One B-rep face of a CAD part: STEP entity #5143.
In plain terms, the planar face has unit normal (-1, 0, 0).
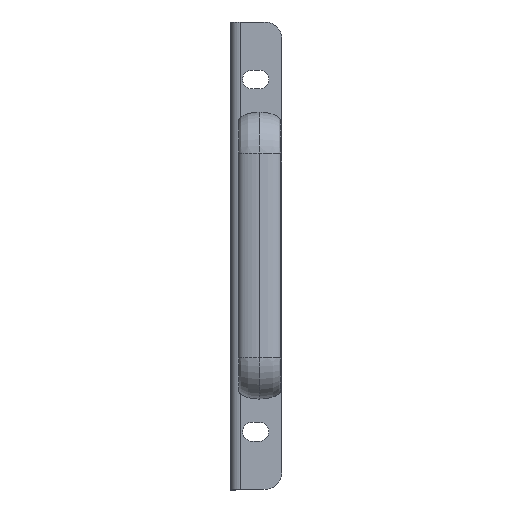
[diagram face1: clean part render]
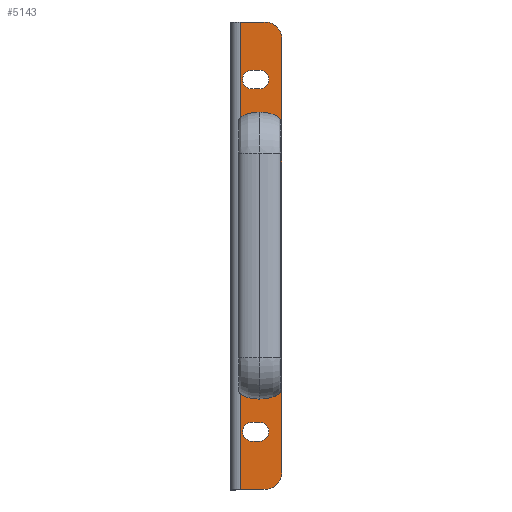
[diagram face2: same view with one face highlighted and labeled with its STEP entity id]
Its self-contained STEP definition (entity closure, numbers rounded to 3 decimals):
#1774=DIRECTION('',(0.,-1.,0.));
#1775=VECTOR('',#1774,177.);
#1776=CARTESIAN_POINT('',(0.,88.5,1.9));
#1777=LINE('',#1776,#1775);
#1792=CARTESIAN_POINT('',(0.,-66.7,6.304));
#1793=DIRECTION('',(-1.,0.,0.));
#1794=DIRECTION('',(0.,1.,0.));
#1795=AXIS2_PLACEMENT_3D('',#1792,#1793,#1794);
#1797=DIRECTION('',(0.,0.,-1.));
#1798=VECTOR('',#1797,2.9);
#1799=CARTESIAN_POINT('',(0.,-70.25,9.204));
#1800=LINE('',#1799,#1798);
#1801=CARTESIAN_POINT('',(0.,-66.7,9.204));
#1802=DIRECTION('',(-1.,0.,0.));
#1803=DIRECTION('',(0.,-1.,0.));
#1804=AXIS2_PLACEMENT_3D('',#1801,#1802,#1803);
#1806=DIRECTION('',(0.,0.,1.));
#1807=VECTOR('',#1806,2.9);
#1808=CARTESIAN_POINT('',(0.,-63.15,6.304));
#1809=LINE('',#1808,#1807);
#1810=DIRECTION('',(0.,0.,1.));
#1811=VECTOR('',#1810,2.9);
#1812=CARTESIAN_POINT('',(0.,70.25,6.304));
#1813=LINE('',#1812,#1811);
#1814=CARTESIAN_POINT('',(0.,66.7,6.304));
#1815=DIRECTION('',(-1.,0.,0.));
#1816=DIRECTION('',(0.,1.,0.));
#1817=AXIS2_PLACEMENT_3D('',#1814,#1815,#1816);
#1819=DIRECTION('',(0.,0.,-1.));
#1820=VECTOR('',#1819,2.9);
#1821=CARTESIAN_POINT('',(0.,63.15,9.204));
#1822=LINE('',#1821,#1820);
#1823=CARTESIAN_POINT('',(0.,66.7,9.204));
#1824=DIRECTION('',(-1.,0.,0.));
#1825=DIRECTION('',(0.,-1.,0.));
#1826=AXIS2_PLACEMENT_3D('',#1823,#1824,#1825);
#1828=CARTESIAN_POINT('',(0.,82.15,11.283));
#1829=DIRECTION('',(-1.,0.,0.));
#1830=DIRECTION('',(0.,0.,1.));
#1831=AXIS2_PLACEMENT_3D('',#1828,#1829,#1830);
#1833=DIRECTION('',(0.,1.,0.));
#1834=VECTOR('',#1833,164.3);
#1835=CARTESIAN_POINT('',(0.,-82.15,17.633));
#1836=LINE('',#1835,#1834);
#1837=CARTESIAN_POINT('',(0.,-82.15,11.283));
#1838=DIRECTION('',(-1.,0.,0.));
#1839=DIRECTION('',(0.,-1.,0.));
#1840=AXIS2_PLACEMENT_3D('',#1837,#1838,#1839);
#1842=DIRECTION('',(0.,0.,1.));
#1843=VECTOR('',#1842,9.383);
#1844=CARTESIAN_POINT('',(0.,-88.5,1.9));
#1845=LINE('',#1844,#1843);
#1846=DIRECTION('',(0.,0.,-1.));
#1847=VECTOR('',#1846,9.383);
#1848=CARTESIAN_POINT('',(0.,88.5,11.283));
#1849=LINE('',#1848,#1847);
#1850=CARTESIAN_POINT('',(0.,50.8,9.382));
#1851=DIRECTION('',(1.,0.,0.));
#1852=DIRECTION('',(0.,0.,1.));
#1853=AXIS2_PLACEMENT_3D('',#1850,#1851,#1852);
#1855=CARTESIAN_POINT('',(0.,50.8,9.382));
#1856=DIRECTION('',(1.,0.,0.));
#1857=DIRECTION('',(0.,0.,-1.));
#1858=AXIS2_PLACEMENT_3D('',#1855,#1856,#1857);
#1860=CARTESIAN_POINT('',(0.,-50.8,9.382));
#1861=DIRECTION('',(1.,0.,0.));
#1862=DIRECTION('',(0.,0.,1.));
#1863=AXIS2_PLACEMENT_3D('',#1860,#1861,#1862);
#1865=CARTESIAN_POINT('',(0.,-50.8,9.382));
#1866=DIRECTION('',(1.,0.,0.));
#1867=DIRECTION('',(0.,0.,-1.));
#1868=AXIS2_PLACEMENT_3D('',#1865,#1866,#1867);
#2294=CARTESIAN_POINT('',(0.,88.5,1.9));
#2295=CARTESIAN_POINT('',(0.,-88.5,1.9));
#2296=VERTEX_POINT('',#2294);
#2297=VERTEX_POINT('',#2295);
#2326=CARTESIAN_POINT('',(0.,70.25,6.304));
#2327=CARTESIAN_POINT('',(0.,70.25,9.204));
#2328=VERTEX_POINT('',#2326);
#2329=VERTEX_POINT('',#2327);
#2330=CARTESIAN_POINT('',(0.,63.15,9.204));
#2331=VERTEX_POINT('',#2330);
#2332=CARTESIAN_POINT('',(0.,63.15,6.304));
#2333=VERTEX_POINT('',#2332);
#2334=CARTESIAN_POINT('',(0.,-63.15,6.304));
#2335=CARTESIAN_POINT('',(0.,-70.25,6.304));
#2336=VERTEX_POINT('',#2334);
#2337=VERTEX_POINT('',#2335);
#2338=CARTESIAN_POINT('',(0.,-63.15,9.204));
#2339=VERTEX_POINT('',#2338);
#2340=CARTESIAN_POINT('',(0.,-70.25,9.204));
#2341=VERTEX_POINT('',#2340);
#2342=CARTESIAN_POINT('',(0.,82.15,17.633));
#2343=CARTESIAN_POINT('',(0.,88.5,11.283));
#2344=VERTEX_POINT('',#2342);
#2345=VERTEX_POINT('',#2343);
#2350=CARTESIAN_POINT('',(0.,-88.5,11.283));
#2351=CARTESIAN_POINT('',(0.,-82.15,17.633));
#2352=VERTEX_POINT('',#2350);
#2353=VERTEX_POINT('',#2351);
#2598=CARTESIAN_POINT('',(0.,-50.8,12.353));
#2599=CARTESIAN_POINT('',(0.,-50.8,6.41));
#2600=VERTEX_POINT('',#2598);
#2601=VERTEX_POINT('',#2599);
#2602=CARTESIAN_POINT('',(0.,50.8,12.353));
#2603=CARTESIAN_POINT('',(0.,50.8,6.41));
#2604=VERTEX_POINT('',#2602);
#2605=VERTEX_POINT('',#2603);
#5093=CARTESIAN_POINT('',(0.,-88.5,-1.9));
#5094=DIRECTION('',(-1.,0.,0.));
#5095=DIRECTION('',(0.,-1.,0.));
#5096=AXIS2_PLACEMENT_3D('',#5093,#5094,#5095);
#5097=PLANE('',#5096);
#5099=ORIENTED_EDGE('',*,*,#5098,.F.);
#5101=ORIENTED_EDGE('',*,*,#5100,.F.);
#5103=ORIENTED_EDGE('',*,*,#5102,.F.);
#5105=ORIENTED_EDGE('',*,*,#5104,.F.);
#5106=ORIENTED_EDGE('',*,*,#5084,.F.);
#5108=ORIENTED_EDGE('',*,*,#5107,.F.);
#5109=EDGE_LOOP('',(#5099,#5101,#5103,#5105,#5106,#5108));
#5110=FACE_OUTER_BOUND('',#5109,.F.);
#5112=ORIENTED_EDGE('',*,*,#5111,.F.);
#5114=ORIENTED_EDGE('',*,*,#5113,.T.);
#5116=ORIENTED_EDGE('',*,*,#5115,.F.);
#5118=ORIENTED_EDGE('',*,*,#5117,.T.);
#5119=EDGE_LOOP('',(#5112,#5114,#5116,#5118));
#5120=FACE_BOUND('',#5119,.F.);
#5122=ORIENTED_EDGE('',*,*,#5121,.T.);
#5124=ORIENTED_EDGE('',*,*,#5123,.F.);
#5126=ORIENTED_EDGE('',*,*,#5125,.T.);
#5128=ORIENTED_EDGE('',*,*,#5127,.F.);
#5129=EDGE_LOOP('',(#5122,#5124,#5126,#5128));
#5130=FACE_BOUND('',#5129,.F.);
#5132=ORIENTED_EDGE('',*,*,#5131,.F.);
#5134=ORIENTED_EDGE('',*,*,#5133,.F.);
#5135=EDGE_LOOP('',(#5132,#5134));
#5136=FACE_BOUND('',#5135,.F.);
#5138=ORIENTED_EDGE('',*,*,#5137,.F.);
#5140=ORIENTED_EDGE('',*,*,#5139,.F.);
#5141=EDGE_LOOP('',(#5138,#5140));
#5142=FACE_BOUND('',#5141,.F.);
#1796=CIRCLE('',#1795,3.55);
#1805=CIRCLE('',#1804,3.55);
#1818=CIRCLE('',#1817,3.55);
#1827=CIRCLE('',#1826,3.55);
#1832=CIRCLE('',#1831,6.35);
#1841=CIRCLE('',#1840,6.35);
#1854=CIRCLE('',#1853,2.972);
#1859=CIRCLE('',#1858,2.972);
#1864=CIRCLE('',#1863,2.972);
#1869=CIRCLE('',#1868,2.972);
#5084=EDGE_CURVE('',#2296,#2297,#1777,.T.);
#5098=EDGE_CURVE('',#2344,#2345,#1832,.T.);
#5100=EDGE_CURVE('',#2353,#2344,#1836,.T.);
#5102=EDGE_CURVE('',#2352,#2353,#1841,.T.);
#5104=EDGE_CURVE('',#2297,#2352,#1845,.T.);
#5107=EDGE_CURVE('',#2345,#2296,#1849,.T.);
#5111=EDGE_CURVE('',#2328,#2329,#1813,.T.);
#5113=EDGE_CURVE('',#2328,#2333,#1818,.T.);
#5115=EDGE_CURVE('',#2331,#2333,#1822,.T.);
#5117=EDGE_CURVE('',#2331,#2329,#1827,.T.);
#5121=EDGE_CURVE('',#2336,#2337,#1796,.T.);
#5123=EDGE_CURVE('',#2341,#2337,#1800,.T.);
#5125=EDGE_CURVE('',#2341,#2339,#1805,.T.);
#5127=EDGE_CURVE('',#2336,#2339,#1809,.T.);
#5131=EDGE_CURVE('',#2604,#2605,#1854,.T.);
#5133=EDGE_CURVE('',#2605,#2604,#1859,.T.);
#5137=EDGE_CURVE('',#2600,#2601,#1864,.T.);
#5139=EDGE_CURVE('',#2601,#2600,#1869,.T.);
#5143=ADVANCED_FACE('',(#5110,#5120,#5130,#5136,#5142),#5097,.T.);
